# Generated by FakeRAM 2.0
VERSION 5.7 ;
BUSBITCHARS "[]" ;
PROPERTYDEFINITIONS
  MACRO width INTEGER ;
  MACRO depth INTEGER ;
  MACRO banks INTEGER ;
END PROPERTYDEFINITIONS
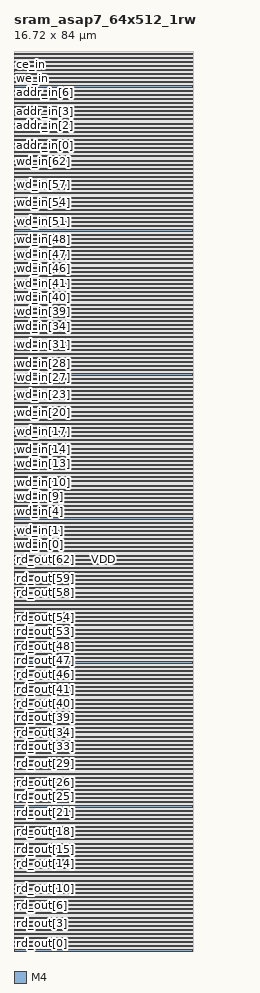
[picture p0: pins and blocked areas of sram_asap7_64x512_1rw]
MACRO sram_asap7_64x512_1rw
  PROPERTY width 64 ;
  PROPERTY depth 512 ;
  PROPERTY banks 2 ;
  FOREIGN sram_asap7_64x512_1rw 0 0 ;
  SYMMETRY X Y R90 ;
  SIZE 16.720 BY 84.000 ;
  CLASS BLOCK ;
  PIN rd_out[0]
    DIRECTION OUTPUT ;
    USE SIGNAL ;
    SHAPE ABUTMENT ;
    PORT
      LAYER M4 ;
      RECT 0.000 0.048 0.024 0.072 ;
    END
  END rd_out[0]
  PIN rd_out[1]
    DIRECTION OUTPUT ;
    USE SIGNAL ;
    SHAPE ABUTMENT ;
    PORT
      LAYER M4 ;
      RECT 0.000 0.624 0.024 0.648 ;
    END
  END rd_out[1]
  PIN rd_out[2]
    DIRECTION OUTPUT ;
    USE SIGNAL ;
    SHAPE ABUTMENT ;
    PORT
      LAYER M4 ;
      RECT 0.000 1.200 0.024 1.224 ;
    END
  END rd_out[2]
  PIN rd_out[3]
    DIRECTION OUTPUT ;
    USE SIGNAL ;
    SHAPE ABUTMENT ;
    PORT
      LAYER M4 ;
      RECT 0.000 1.776 0.024 1.800 ;
    END
  END rd_out[3]
  PIN rd_out[4]
    DIRECTION OUTPUT ;
    USE SIGNAL ;
    SHAPE ABUTMENT ;
    PORT
      LAYER M4 ;
      RECT 0.000 2.352 0.024 2.376 ;
    END
  END rd_out[4]
  PIN rd_out[5]
    DIRECTION OUTPUT ;
    USE SIGNAL ;
    SHAPE ABUTMENT ;
    PORT
      LAYER M4 ;
      RECT 0.000 2.928 0.024 2.952 ;
    END
  END rd_out[5]
  PIN rd_out[6]
    DIRECTION OUTPUT ;
    USE SIGNAL ;
    SHAPE ABUTMENT ;
    PORT
      LAYER M4 ;
      RECT 0.000 3.504 0.024 3.528 ;
    END
  END rd_out[6]
  PIN rd_out[7]
    DIRECTION OUTPUT ;
    USE SIGNAL ;
    SHAPE ABUTMENT ;
    PORT
      LAYER M4 ;
      RECT 0.000 4.080 0.024 4.104 ;
    END
  END rd_out[7]
  PIN rd_out[8]
    DIRECTION OUTPUT ;
    USE SIGNAL ;
    SHAPE ABUTMENT ;
    PORT
      LAYER M4 ;
      RECT 0.000 4.656 0.024 4.680 ;
    END
  END rd_out[8]
  PIN rd_out[9]
    DIRECTION OUTPUT ;
    USE SIGNAL ;
    SHAPE ABUTMENT ;
    PORT
      LAYER M4 ;
      RECT 0.000 5.232 0.024 5.256 ;
    END
  END rd_out[9]
  PIN rd_out[10]
    DIRECTION OUTPUT ;
    USE SIGNAL ;
    SHAPE ABUTMENT ;
    PORT
      LAYER M4 ;
      RECT 0.000 5.808 0.024 5.832 ;
    END
  END rd_out[10]
  PIN rd_out[11]
    DIRECTION OUTPUT ;
    USE SIGNAL ;
    SHAPE ABUTMENT ;
    PORT
      LAYER M4 ;
      RECT 0.000 6.384 0.024 6.408 ;
    END
  END rd_out[11]
  PIN rd_out[12]
    DIRECTION OUTPUT ;
    USE SIGNAL ;
    SHAPE ABUTMENT ;
    PORT
      LAYER M4 ;
      RECT 0.000 6.960 0.024 6.984 ;
    END
  END rd_out[12]
  PIN rd_out[13]
    DIRECTION OUTPUT ;
    USE SIGNAL ;
    SHAPE ABUTMENT ;
    PORT
      LAYER M4 ;
      RECT 0.000 7.536 0.024 7.560 ;
    END
  END rd_out[13]
  PIN rd_out[14]
    DIRECTION OUTPUT ;
    USE SIGNAL ;
    SHAPE ABUTMENT ;
    PORT
      LAYER M4 ;
      RECT 0.000 8.112 0.024 8.136 ;
    END
  END rd_out[14]
  PIN rd_out[15]
    DIRECTION OUTPUT ;
    USE SIGNAL ;
    SHAPE ABUTMENT ;
    PORT
      LAYER M4 ;
      RECT 0.000 8.688 0.024 8.712 ;
    END
  END rd_out[15]
  PIN rd_out[16]
    DIRECTION OUTPUT ;
    USE SIGNAL ;
    SHAPE ABUTMENT ;
    PORT
      LAYER M4 ;
      RECT 0.000 9.264 0.024 9.288 ;
    END
  END rd_out[16]
  PIN rd_out[17]
    DIRECTION OUTPUT ;
    USE SIGNAL ;
    SHAPE ABUTMENT ;
    PORT
      LAYER M4 ;
      RECT 0.000 9.840 0.024 9.864 ;
    END
  END rd_out[17]
  PIN rd_out[18]
    DIRECTION OUTPUT ;
    USE SIGNAL ;
    SHAPE ABUTMENT ;
    PORT
      LAYER M4 ;
      RECT 0.000 10.416 0.024 10.440 ;
    END
  END rd_out[18]
  PIN rd_out[19]
    DIRECTION OUTPUT ;
    USE SIGNAL ;
    SHAPE ABUTMENT ;
    PORT
      LAYER M4 ;
      RECT 0.000 10.992 0.024 11.016 ;
    END
  END rd_out[19]
  PIN rd_out[20]
    DIRECTION OUTPUT ;
    USE SIGNAL ;
    SHAPE ABUTMENT ;
    PORT
      LAYER M4 ;
      RECT 0.000 11.568 0.024 11.592 ;
    END
  END rd_out[20]
  PIN rd_out[21]
    DIRECTION OUTPUT ;
    USE SIGNAL ;
    SHAPE ABUTMENT ;
    PORT
      LAYER M4 ;
      RECT 0.000 12.144 0.024 12.168 ;
    END
  END rd_out[21]
  PIN rd_out[22]
    DIRECTION OUTPUT ;
    USE SIGNAL ;
    SHAPE ABUTMENT ;
    PORT
      LAYER M4 ;
      RECT 0.000 12.720 0.024 12.744 ;
    END
  END rd_out[22]
  PIN rd_out[23]
    DIRECTION OUTPUT ;
    USE SIGNAL ;
    SHAPE ABUTMENT ;
    PORT
      LAYER M4 ;
      RECT 0.000 13.296 0.024 13.320 ;
    END
  END rd_out[23]
  PIN rd_out[24]
    DIRECTION OUTPUT ;
    USE SIGNAL ;
    SHAPE ABUTMENT ;
    PORT
      LAYER M4 ;
      RECT 0.000 13.872 0.024 13.896 ;
    END
  END rd_out[24]
  PIN rd_out[25]
    DIRECTION OUTPUT ;
    USE SIGNAL ;
    SHAPE ABUTMENT ;
    PORT
      LAYER M4 ;
      RECT 0.000 14.448 0.024 14.472 ;
    END
  END rd_out[25]
  PIN rd_out[26]
    DIRECTION OUTPUT ;
    USE SIGNAL ;
    SHAPE ABUTMENT ;
    PORT
      LAYER M4 ;
      RECT 0.000 15.024 0.024 15.048 ;
    END
  END rd_out[26]
  PIN rd_out[27]
    DIRECTION OUTPUT ;
    USE SIGNAL ;
    SHAPE ABUTMENT ;
    PORT
      LAYER M4 ;
      RECT 0.000 15.600 0.024 15.624 ;
    END
  END rd_out[27]
  PIN rd_out[28]
    DIRECTION OUTPUT ;
    USE SIGNAL ;
    SHAPE ABUTMENT ;
    PORT
      LAYER M4 ;
      RECT 0.000 16.176 0.024 16.200 ;
    END
  END rd_out[28]
  PIN rd_out[29]
    DIRECTION OUTPUT ;
    USE SIGNAL ;
    SHAPE ABUTMENT ;
    PORT
      LAYER M4 ;
      RECT 0.000 16.752 0.024 16.776 ;
    END
  END rd_out[29]
  PIN rd_out[30]
    DIRECTION OUTPUT ;
    USE SIGNAL ;
    SHAPE ABUTMENT ;
    PORT
      LAYER M4 ;
      RECT 0.000 17.328 0.024 17.352 ;
    END
  END rd_out[30]
  PIN rd_out[31]
    DIRECTION OUTPUT ;
    USE SIGNAL ;
    SHAPE ABUTMENT ;
    PORT
      LAYER M4 ;
      RECT 0.000 17.904 0.024 17.928 ;
    END
  END rd_out[31]
  PIN rd_out[32]
    DIRECTION OUTPUT ;
    USE SIGNAL ;
    SHAPE ABUTMENT ;
    PORT
      LAYER M4 ;
      RECT 0.000 18.480 0.024 18.504 ;
    END
  END rd_out[32]
  PIN rd_out[33]
    DIRECTION OUTPUT ;
    USE SIGNAL ;
    SHAPE ABUTMENT ;
    PORT
      LAYER M4 ;
      RECT 0.000 19.056 0.024 19.080 ;
    END
  END rd_out[33]
  PIN rd_out[34]
    DIRECTION OUTPUT ;
    USE SIGNAL ;
    SHAPE ABUTMENT ;
    PORT
      LAYER M4 ;
      RECT 0.000 19.632 0.024 19.656 ;
    END
  END rd_out[34]
  PIN rd_out[35]
    DIRECTION OUTPUT ;
    USE SIGNAL ;
    SHAPE ABUTMENT ;
    PORT
      LAYER M4 ;
      RECT 0.000 20.208 0.024 20.232 ;
    END
  END rd_out[35]
  PIN rd_out[36]
    DIRECTION OUTPUT ;
    USE SIGNAL ;
    SHAPE ABUTMENT ;
    PORT
      LAYER M4 ;
      RECT 0.000 20.784 0.024 20.808 ;
    END
  END rd_out[36]
  PIN rd_out[37]
    DIRECTION OUTPUT ;
    USE SIGNAL ;
    SHAPE ABUTMENT ;
    PORT
      LAYER M4 ;
      RECT 0.000 21.360 0.024 21.384 ;
    END
  END rd_out[37]
  PIN rd_out[38]
    DIRECTION OUTPUT ;
    USE SIGNAL ;
    SHAPE ABUTMENT ;
    PORT
      LAYER M4 ;
      RECT 0.000 21.936 0.024 21.960 ;
    END
  END rd_out[38]
  PIN rd_out[39]
    DIRECTION OUTPUT ;
    USE SIGNAL ;
    SHAPE ABUTMENT ;
    PORT
      LAYER M4 ;
      RECT 0.000 22.512 0.024 22.536 ;
    END
  END rd_out[39]
  PIN rd_out[40]
    DIRECTION OUTPUT ;
    USE SIGNAL ;
    SHAPE ABUTMENT ;
    PORT
      LAYER M4 ;
      RECT 0.000 23.088 0.024 23.112 ;
    END
  END rd_out[40]
  PIN rd_out[41]
    DIRECTION OUTPUT ;
    USE SIGNAL ;
    SHAPE ABUTMENT ;
    PORT
      LAYER M4 ;
      RECT 0.000 23.664 0.024 23.688 ;
    END
  END rd_out[41]
  PIN rd_out[42]
    DIRECTION OUTPUT ;
    USE SIGNAL ;
    SHAPE ABUTMENT ;
    PORT
      LAYER M4 ;
      RECT 0.000 24.240 0.024 24.264 ;
    END
  END rd_out[42]
  PIN rd_out[43]
    DIRECTION OUTPUT ;
    USE SIGNAL ;
    SHAPE ABUTMENT ;
    PORT
      LAYER M4 ;
      RECT 0.000 24.816 0.024 24.840 ;
    END
  END rd_out[43]
  PIN rd_out[44]
    DIRECTION OUTPUT ;
    USE SIGNAL ;
    SHAPE ABUTMENT ;
    PORT
      LAYER M4 ;
      RECT 0.000 25.392 0.024 25.416 ;
    END
  END rd_out[44]
  PIN rd_out[45]
    DIRECTION OUTPUT ;
    USE SIGNAL ;
    SHAPE ABUTMENT ;
    PORT
      LAYER M4 ;
      RECT 0.000 25.968 0.024 25.992 ;
    END
  END rd_out[45]
  PIN rd_out[46]
    DIRECTION OUTPUT ;
    USE SIGNAL ;
    SHAPE ABUTMENT ;
    PORT
      LAYER M4 ;
      RECT 0.000 26.544 0.024 26.568 ;
    END
  END rd_out[46]
  PIN rd_out[47]
    DIRECTION OUTPUT ;
    USE SIGNAL ;
    SHAPE ABUTMENT ;
    PORT
      LAYER M4 ;
      RECT 0.000 27.120 0.024 27.144 ;
    END
  END rd_out[47]
  PIN rd_out[48]
    DIRECTION OUTPUT ;
    USE SIGNAL ;
    SHAPE ABUTMENT ;
    PORT
      LAYER M4 ;
      RECT 0.000 27.696 0.024 27.720 ;
    END
  END rd_out[48]
  PIN rd_out[49]
    DIRECTION OUTPUT ;
    USE SIGNAL ;
    SHAPE ABUTMENT ;
    PORT
      LAYER M4 ;
      RECT 0.000 28.272 0.024 28.296 ;
    END
  END rd_out[49]
  PIN rd_out[50]
    DIRECTION OUTPUT ;
    USE SIGNAL ;
    SHAPE ABUTMENT ;
    PORT
      LAYER M4 ;
      RECT 0.000 28.848 0.024 28.872 ;
    END
  END rd_out[50]
  PIN rd_out[51]
    DIRECTION OUTPUT ;
    USE SIGNAL ;
    SHAPE ABUTMENT ;
    PORT
      LAYER M4 ;
      RECT 0.000 29.424 0.024 29.448 ;
    END
  END rd_out[51]
  PIN rd_out[52]
    DIRECTION OUTPUT ;
    USE SIGNAL ;
    SHAPE ABUTMENT ;
    PORT
      LAYER M4 ;
      RECT 0.000 30.000 0.024 30.024 ;
    END
  END rd_out[52]
  PIN rd_out[53]
    DIRECTION OUTPUT ;
    USE SIGNAL ;
    SHAPE ABUTMENT ;
    PORT
      LAYER M4 ;
      RECT 0.000 30.576 0.024 30.600 ;
    END
  END rd_out[53]
  PIN rd_out[54]
    DIRECTION OUTPUT ;
    USE SIGNAL ;
    SHAPE ABUTMENT ;
    PORT
      LAYER M4 ;
      RECT 0.000 31.152 0.024 31.176 ;
    END
  END rd_out[54]
  PIN rd_out[55]
    DIRECTION OUTPUT ;
    USE SIGNAL ;
    SHAPE ABUTMENT ;
    PORT
      LAYER M4 ;
      RECT 0.000 31.728 0.024 31.752 ;
    END
  END rd_out[55]
  PIN rd_out[56]
    DIRECTION OUTPUT ;
    USE SIGNAL ;
    SHAPE ABUTMENT ;
    PORT
      LAYER M4 ;
      RECT 0.000 32.304 0.024 32.328 ;
    END
  END rd_out[56]
  PIN rd_out[57]
    DIRECTION OUTPUT ;
    USE SIGNAL ;
    SHAPE ABUTMENT ;
    PORT
      LAYER M4 ;
      RECT 0.000 32.880 0.024 32.904 ;
    END
  END rd_out[57]
  PIN rd_out[58]
    DIRECTION OUTPUT ;
    USE SIGNAL ;
    SHAPE ABUTMENT ;
    PORT
      LAYER M4 ;
      RECT 0.000 33.456 0.024 33.480 ;
    END
  END rd_out[58]
  PIN rd_out[59]
    DIRECTION OUTPUT ;
    USE SIGNAL ;
    SHAPE ABUTMENT ;
    PORT
      LAYER M4 ;
      RECT 0.000 34.032 0.024 34.056 ;
    END
  END rd_out[59]
  PIN rd_out[60]
    DIRECTION OUTPUT ;
    USE SIGNAL ;
    SHAPE ABUTMENT ;
    PORT
      LAYER M4 ;
      RECT 0.000 34.608 0.024 34.632 ;
    END
  END rd_out[60]
  PIN rd_out[61]
    DIRECTION OUTPUT ;
    USE SIGNAL ;
    SHAPE ABUTMENT ;
    PORT
      LAYER M4 ;
      RECT 0.000 35.184 0.024 35.208 ;
    END
  END rd_out[61]
  PIN rd_out[62]
    DIRECTION OUTPUT ;
    USE SIGNAL ;
    SHAPE ABUTMENT ;
    PORT
      LAYER M4 ;
      RECT 0.000 35.760 0.024 35.784 ;
    END
  END rd_out[62]
  PIN rd_out[63]
    DIRECTION OUTPUT ;
    USE SIGNAL ;
    SHAPE ABUTMENT ;
    PORT
      LAYER M4 ;
      RECT 0.000 36.336 0.024 36.360 ;
    END
  END rd_out[63]
  PIN wd_in[0]
    DIRECTION INPUT ;
    USE SIGNAL ;
    SHAPE ABUTMENT ;
    PORT
      LAYER M4 ;
      RECT 0.000 37.968 0.024 37.992 ;
    END
  END wd_in[0]
  PIN wd_in[1]
    DIRECTION INPUT ;
    USE SIGNAL ;
    SHAPE ABUTMENT ;
    PORT
      LAYER M4 ;
      RECT 0.000 38.544 0.024 38.568 ;
    END
  END wd_in[1]
  PIN wd_in[2]
    DIRECTION INPUT ;
    USE SIGNAL ;
    SHAPE ABUTMENT ;
    PORT
      LAYER M4 ;
      RECT 0.000 39.120 0.024 39.144 ;
    END
  END wd_in[2]
  PIN wd_in[3]
    DIRECTION INPUT ;
    USE SIGNAL ;
    SHAPE ABUTMENT ;
    PORT
      LAYER M4 ;
      RECT 0.000 39.696 0.024 39.720 ;
    END
  END wd_in[3]
  PIN wd_in[4]
    DIRECTION INPUT ;
    USE SIGNAL ;
    SHAPE ABUTMENT ;
    PORT
      LAYER M4 ;
      RECT 0.000 40.272 0.024 40.296 ;
    END
  END wd_in[4]
  PIN wd_in[5]
    DIRECTION INPUT ;
    USE SIGNAL ;
    SHAPE ABUTMENT ;
    PORT
      LAYER M4 ;
      RECT 0.000 40.848 0.024 40.872 ;
    END
  END wd_in[5]
  PIN wd_in[6]
    DIRECTION INPUT ;
    USE SIGNAL ;
    SHAPE ABUTMENT ;
    PORT
      LAYER M4 ;
      RECT 0.000 41.424 0.024 41.448 ;
    END
  END wd_in[6]
  PIN wd_in[7]
    DIRECTION INPUT ;
    USE SIGNAL ;
    SHAPE ABUTMENT ;
    PORT
      LAYER M4 ;
      RECT 0.000 42.000 0.024 42.024 ;
    END
  END wd_in[7]
  PIN wd_in[8]
    DIRECTION INPUT ;
    USE SIGNAL ;
    SHAPE ABUTMENT ;
    PORT
      LAYER M4 ;
      RECT 0.000 42.576 0.024 42.600 ;
    END
  END wd_in[8]
  PIN wd_in[9]
    DIRECTION INPUT ;
    USE SIGNAL ;
    SHAPE ABUTMENT ;
    PORT
      LAYER M4 ;
      RECT 0.000 43.152 0.024 43.176 ;
    END
  END wd_in[9]
  PIN wd_in[10]
    DIRECTION INPUT ;
    USE SIGNAL ;
    SHAPE ABUTMENT ;
    PORT
      LAYER M4 ;
      RECT 0.000 43.728 0.024 43.752 ;
    END
  END wd_in[10]
  PIN wd_in[11]
    DIRECTION INPUT ;
    USE SIGNAL ;
    SHAPE ABUTMENT ;
    PORT
      LAYER M4 ;
      RECT 0.000 44.304 0.024 44.328 ;
    END
  END wd_in[11]
  PIN wd_in[12]
    DIRECTION INPUT ;
    USE SIGNAL ;
    SHAPE ABUTMENT ;
    PORT
      LAYER M4 ;
      RECT 0.000 44.880 0.024 44.904 ;
    END
  END wd_in[12]
  PIN wd_in[13]
    DIRECTION INPUT ;
    USE SIGNAL ;
    SHAPE ABUTMENT ;
    PORT
      LAYER M4 ;
      RECT 0.000 45.456 0.024 45.480 ;
    END
  END wd_in[13]
  PIN wd_in[14]
    DIRECTION INPUT ;
    USE SIGNAL ;
    SHAPE ABUTMENT ;
    PORT
      LAYER M4 ;
      RECT 0.000 46.032 0.024 46.056 ;
    END
  END wd_in[14]
  PIN wd_in[15]
    DIRECTION INPUT ;
    USE SIGNAL ;
    SHAPE ABUTMENT ;
    PORT
      LAYER M4 ;
      RECT 0.000 46.608 0.024 46.632 ;
    END
  END wd_in[15]
  PIN wd_in[16]
    DIRECTION INPUT ;
    USE SIGNAL ;
    SHAPE ABUTMENT ;
    PORT
      LAYER M4 ;
      RECT 0.000 47.184 0.024 47.208 ;
    END
  END wd_in[16]
  PIN wd_in[17]
    DIRECTION INPUT ;
    USE SIGNAL ;
    SHAPE ABUTMENT ;
    PORT
      LAYER M4 ;
      RECT 0.000 47.760 0.024 47.784 ;
    END
  END wd_in[17]
  PIN wd_in[18]
    DIRECTION INPUT ;
    USE SIGNAL ;
    SHAPE ABUTMENT ;
    PORT
      LAYER M4 ;
      RECT 0.000 48.336 0.024 48.360 ;
    END
  END wd_in[18]
  PIN wd_in[19]
    DIRECTION INPUT ;
    USE SIGNAL ;
    SHAPE ABUTMENT ;
    PORT
      LAYER M4 ;
      RECT 0.000 48.912 0.024 48.936 ;
    END
  END wd_in[19]
  PIN wd_in[20]
    DIRECTION INPUT ;
    USE SIGNAL ;
    SHAPE ABUTMENT ;
    PORT
      LAYER M4 ;
      RECT 0.000 49.488 0.024 49.512 ;
    END
  END wd_in[20]
  PIN wd_in[21]
    DIRECTION INPUT ;
    USE SIGNAL ;
    SHAPE ABUTMENT ;
    PORT
      LAYER M4 ;
      RECT 0.000 50.064 0.024 50.088 ;
    END
  END wd_in[21]
  PIN wd_in[22]
    DIRECTION INPUT ;
    USE SIGNAL ;
    SHAPE ABUTMENT ;
    PORT
      LAYER M4 ;
      RECT 0.000 50.640 0.024 50.664 ;
    END
  END wd_in[22]
  PIN wd_in[23]
    DIRECTION INPUT ;
    USE SIGNAL ;
    SHAPE ABUTMENT ;
    PORT
      LAYER M4 ;
      RECT 0.000 51.216 0.024 51.240 ;
    END
  END wd_in[23]
  PIN wd_in[24]
    DIRECTION INPUT ;
    USE SIGNAL ;
    SHAPE ABUTMENT ;
    PORT
      LAYER M4 ;
      RECT 0.000 51.792 0.024 51.816 ;
    END
  END wd_in[24]
  PIN wd_in[25]
    DIRECTION INPUT ;
    USE SIGNAL ;
    SHAPE ABUTMENT ;
    PORT
      LAYER M4 ;
      RECT 0.000 52.368 0.024 52.392 ;
    END
  END wd_in[25]
  PIN wd_in[26]
    DIRECTION INPUT ;
    USE SIGNAL ;
    SHAPE ABUTMENT ;
    PORT
      LAYER M4 ;
      RECT 0.000 52.944 0.024 52.968 ;
    END
  END wd_in[26]
  PIN wd_in[27]
    DIRECTION INPUT ;
    USE SIGNAL ;
    SHAPE ABUTMENT ;
    PORT
      LAYER M4 ;
      RECT 0.000 53.520 0.024 53.544 ;
    END
  END wd_in[27]
  PIN wd_in[28]
    DIRECTION INPUT ;
    USE SIGNAL ;
    SHAPE ABUTMENT ;
    PORT
      LAYER M4 ;
      RECT 0.000 54.096 0.024 54.120 ;
    END
  END wd_in[28]
  PIN wd_in[29]
    DIRECTION INPUT ;
    USE SIGNAL ;
    SHAPE ABUTMENT ;
    PORT
      LAYER M4 ;
      RECT 0.000 54.672 0.024 54.696 ;
    END
  END wd_in[29]
  PIN wd_in[30]
    DIRECTION INPUT ;
    USE SIGNAL ;
    SHAPE ABUTMENT ;
    PORT
      LAYER M4 ;
      RECT 0.000 55.248 0.024 55.272 ;
    END
  END wd_in[30]
  PIN wd_in[31]
    DIRECTION INPUT ;
    USE SIGNAL ;
    SHAPE ABUTMENT ;
    PORT
      LAYER M4 ;
      RECT 0.000 55.824 0.024 55.848 ;
    END
  END wd_in[31]
  PIN wd_in[32]
    DIRECTION INPUT ;
    USE SIGNAL ;
    SHAPE ABUTMENT ;
    PORT
      LAYER M4 ;
      RECT 0.000 56.400 0.024 56.424 ;
    END
  END wd_in[32]
  PIN wd_in[33]
    DIRECTION INPUT ;
    USE SIGNAL ;
    SHAPE ABUTMENT ;
    PORT
      LAYER M4 ;
      RECT 0.000 56.976 0.024 57.000 ;
    END
  END wd_in[33]
  PIN wd_in[34]
    DIRECTION INPUT ;
    USE SIGNAL ;
    SHAPE ABUTMENT ;
    PORT
      LAYER M4 ;
      RECT 0.000 57.552 0.024 57.576 ;
    END
  END wd_in[34]
  PIN wd_in[35]
    DIRECTION INPUT ;
    USE SIGNAL ;
    SHAPE ABUTMENT ;
    PORT
      LAYER M4 ;
      RECT 0.000 58.128 0.024 58.152 ;
    END
  END wd_in[35]
  PIN wd_in[36]
    DIRECTION INPUT ;
    USE SIGNAL ;
    SHAPE ABUTMENT ;
    PORT
      LAYER M4 ;
      RECT 0.000 58.704 0.024 58.728 ;
    END
  END wd_in[36]
  PIN wd_in[37]
    DIRECTION INPUT ;
    USE SIGNAL ;
    SHAPE ABUTMENT ;
    PORT
      LAYER M4 ;
      RECT 0.000 59.280 0.024 59.304 ;
    END
  END wd_in[37]
  PIN wd_in[38]
    DIRECTION INPUT ;
    USE SIGNAL ;
    SHAPE ABUTMENT ;
    PORT
      LAYER M4 ;
      RECT 0.000 59.856 0.024 59.880 ;
    END
  END wd_in[38]
  PIN wd_in[39]
    DIRECTION INPUT ;
    USE SIGNAL ;
    SHAPE ABUTMENT ;
    PORT
      LAYER M4 ;
      RECT 0.000 60.432 0.024 60.456 ;
    END
  END wd_in[39]
  PIN wd_in[40]
    DIRECTION INPUT ;
    USE SIGNAL ;
    SHAPE ABUTMENT ;
    PORT
      LAYER M4 ;
      RECT 0.000 61.008 0.024 61.032 ;
    END
  END wd_in[40]
  PIN wd_in[41]
    DIRECTION INPUT ;
    USE SIGNAL ;
    SHAPE ABUTMENT ;
    PORT
      LAYER M4 ;
      RECT 0.000 61.584 0.024 61.608 ;
    END
  END wd_in[41]
  PIN wd_in[42]
    DIRECTION INPUT ;
    USE SIGNAL ;
    SHAPE ABUTMENT ;
    PORT
      LAYER M4 ;
      RECT 0.000 62.160 0.024 62.184 ;
    END
  END wd_in[42]
  PIN wd_in[43]
    DIRECTION INPUT ;
    USE SIGNAL ;
    SHAPE ABUTMENT ;
    PORT
      LAYER M4 ;
      RECT 0.000 62.736 0.024 62.760 ;
    END
  END wd_in[43]
  PIN wd_in[44]
    DIRECTION INPUT ;
    USE SIGNAL ;
    SHAPE ABUTMENT ;
    PORT
      LAYER M4 ;
      RECT 0.000 63.312 0.024 63.336 ;
    END
  END wd_in[44]
  PIN wd_in[45]
    DIRECTION INPUT ;
    USE SIGNAL ;
    SHAPE ABUTMENT ;
    PORT
      LAYER M4 ;
      RECT 0.000 63.888 0.024 63.912 ;
    END
  END wd_in[45]
  PIN wd_in[46]
    DIRECTION INPUT ;
    USE SIGNAL ;
    SHAPE ABUTMENT ;
    PORT
      LAYER M4 ;
      RECT 0.000 64.464 0.024 64.488 ;
    END
  END wd_in[46]
  PIN wd_in[47]
    DIRECTION INPUT ;
    USE SIGNAL ;
    SHAPE ABUTMENT ;
    PORT
      LAYER M4 ;
      RECT 0.000 65.040 0.024 65.064 ;
    END
  END wd_in[47]
  PIN wd_in[48]
    DIRECTION INPUT ;
    USE SIGNAL ;
    SHAPE ABUTMENT ;
    PORT
      LAYER M4 ;
      RECT 0.000 65.616 0.024 65.640 ;
    END
  END wd_in[48]
  PIN wd_in[49]
    DIRECTION INPUT ;
    USE SIGNAL ;
    SHAPE ABUTMENT ;
    PORT
      LAYER M4 ;
      RECT 0.000 66.192 0.024 66.216 ;
    END
  END wd_in[49]
  PIN wd_in[50]
    DIRECTION INPUT ;
    USE SIGNAL ;
    SHAPE ABUTMENT ;
    PORT
      LAYER M4 ;
      RECT 0.000 66.768 0.024 66.792 ;
    END
  END wd_in[50]
  PIN wd_in[51]
    DIRECTION INPUT ;
    USE SIGNAL ;
    SHAPE ABUTMENT ;
    PORT
      LAYER M4 ;
      RECT 0.000 67.344 0.024 67.368 ;
    END
  END wd_in[51]
  PIN wd_in[52]
    DIRECTION INPUT ;
    USE SIGNAL ;
    SHAPE ABUTMENT ;
    PORT
      LAYER M4 ;
      RECT 0.000 67.920 0.024 67.944 ;
    END
  END wd_in[52]
  PIN wd_in[53]
    DIRECTION INPUT ;
    USE SIGNAL ;
    SHAPE ABUTMENT ;
    PORT
      LAYER M4 ;
      RECT 0.000 68.496 0.024 68.520 ;
    END
  END wd_in[53]
  PIN wd_in[54]
    DIRECTION INPUT ;
    USE SIGNAL ;
    SHAPE ABUTMENT ;
    PORT
      LAYER M4 ;
      RECT 0.000 69.072 0.024 69.096 ;
    END
  END wd_in[54]
  PIN wd_in[55]
    DIRECTION INPUT ;
    USE SIGNAL ;
    SHAPE ABUTMENT ;
    PORT
      LAYER M4 ;
      RECT 0.000 69.648 0.024 69.672 ;
    END
  END wd_in[55]
  PIN wd_in[56]
    DIRECTION INPUT ;
    USE SIGNAL ;
    SHAPE ABUTMENT ;
    PORT
      LAYER M4 ;
      RECT 0.000 70.224 0.024 70.248 ;
    END
  END wd_in[56]
  PIN wd_in[57]
    DIRECTION INPUT ;
    USE SIGNAL ;
    SHAPE ABUTMENT ;
    PORT
      LAYER M4 ;
      RECT 0.000 70.800 0.024 70.824 ;
    END
  END wd_in[57]
  PIN wd_in[58]
    DIRECTION INPUT ;
    USE SIGNAL ;
    SHAPE ABUTMENT ;
    PORT
      LAYER M4 ;
      RECT 0.000 71.376 0.024 71.400 ;
    END
  END wd_in[58]
  PIN wd_in[59]
    DIRECTION INPUT ;
    USE SIGNAL ;
    SHAPE ABUTMENT ;
    PORT
      LAYER M4 ;
      RECT 0.000 71.952 0.024 71.976 ;
    END
  END wd_in[59]
  PIN wd_in[60]
    DIRECTION INPUT ;
    USE SIGNAL ;
    SHAPE ABUTMENT ;
    PORT
      LAYER M4 ;
      RECT 0.000 72.528 0.024 72.552 ;
    END
  END wd_in[60]
  PIN wd_in[61]
    DIRECTION INPUT ;
    USE SIGNAL ;
    SHAPE ABUTMENT ;
    PORT
      LAYER M4 ;
      RECT 0.000 73.104 0.024 73.128 ;
    END
  END wd_in[61]
  PIN wd_in[62]
    DIRECTION INPUT ;
    USE SIGNAL ;
    SHAPE ABUTMENT ;
    PORT
      LAYER M4 ;
      RECT 0.000 73.680 0.024 73.704 ;
    END
  END wd_in[62]
  PIN wd_in[63]
    DIRECTION INPUT ;
    USE SIGNAL ;
    SHAPE ABUTMENT ;
    PORT
      LAYER M4 ;
      RECT 0.000 74.256 0.024 74.280 ;
    END
  END wd_in[63]
  PIN addr_in[0]
    DIRECTION INPUT ;
    USE SIGNAL ;
    SHAPE ABUTMENT ;
    PORT
      LAYER M4 ;
      RECT 0.000 75.888 0.024 75.912 ;
    END
  END addr_in[0]
  PIN addr_in[1]
    DIRECTION INPUT ;
    USE SIGNAL ;
    SHAPE ABUTMENT ;
    PORT
      LAYER M4 ;
      RECT 0.000 76.464 0.024 76.488 ;
    END
  END addr_in[1]
  PIN addr_in[2]
    DIRECTION INPUT ;
    USE SIGNAL ;
    SHAPE ABUTMENT ;
    PORT
      LAYER M4 ;
      RECT 0.000 77.040 0.024 77.064 ;
    END
  END addr_in[2]
  PIN addr_in[3]
    DIRECTION INPUT ;
    USE SIGNAL ;
    SHAPE ABUTMENT ;
    PORT
      LAYER M4 ;
      RECT 0.000 77.616 0.024 77.640 ;
    END
  END addr_in[3]
  PIN addr_in[4]
    DIRECTION INPUT ;
    USE SIGNAL ;
    SHAPE ABUTMENT ;
    PORT
      LAYER M4 ;
      RECT 0.000 78.192 0.024 78.216 ;
    END
  END addr_in[4]
  PIN addr_in[5]
    DIRECTION INPUT ;
    USE SIGNAL ;
    SHAPE ABUTMENT ;
    PORT
      LAYER M4 ;
      RECT 0.000 78.768 0.024 78.792 ;
    END
  END addr_in[5]
  PIN addr_in[6]
    DIRECTION INPUT ;
    USE SIGNAL ;
    SHAPE ABUTMENT ;
    PORT
      LAYER M4 ;
      RECT 0.000 79.344 0.024 79.368 ;
    END
  END addr_in[6]
  PIN addr_in[7]
    DIRECTION INPUT ;
    USE SIGNAL ;
    SHAPE ABUTMENT ;
    PORT
      LAYER M4 ;
      RECT 0.000 79.920 0.024 79.944 ;
    END
  END addr_in[7]
  PIN addr_in[8]
    DIRECTION INPUT ;
    USE SIGNAL ;
    SHAPE ABUTMENT ;
    PORT
      LAYER M4 ;
      RECT 0.000 80.496 0.024 80.520 ;
    END
  END addr_in[8]
  PIN we_in
    DIRECTION INPUT ;
    USE SIGNAL ;
    SHAPE ABUTMENT ;
    PORT
      LAYER M4 ;
      RECT 0.000 82.128 0.024 82.152 ;
    END
  END we_in
  PIN ce_in
    DIRECTION INPUT ;
    USE SIGNAL ;
    SHAPE ABUTMENT ;
    PORT
      LAYER M4 ;
      RECT 0.000 82.704 0.024 82.728 ;
    END
  END ce_in
  PIN clk
    DIRECTION INPUT ;
    USE SIGNAL ;
    SHAPE ABUTMENT ;
    PORT
      LAYER M4 ;
      RECT 0.000 83.280 0.024 83.304 ;
    END
  END clk
  PIN VSS
    DIRECTION INOUT ;
    USE GROUND ;
    PORT
      LAYER M4 ;
      RECT 0.048 0.000 16.672 0.096 ;
      RECT 0.048 0.768 16.672 0.864 ;
      RECT 0.048 1.536 16.672 1.632 ;
      RECT 0.048 2.304 16.672 2.400 ;
      RECT 0.048 3.072 16.672 3.168 ;
      RECT 0.048 3.840 16.672 3.936 ;
      RECT 0.048 4.608 16.672 4.704 ;
      RECT 0.048 5.376 16.672 5.472 ;
      RECT 0.048 6.144 16.672 6.240 ;
      RECT 0.048 6.912 16.672 7.008 ;
      RECT 0.048 7.680 16.672 7.776 ;
      RECT 0.048 8.448 16.672 8.544 ;
      RECT 0.048 9.216 16.672 9.312 ;
      RECT 0.048 9.984 16.672 10.080 ;
      RECT 0.048 10.752 16.672 10.848 ;
      RECT 0.048 11.520 16.672 11.616 ;
      RECT 0.048 12.288 16.672 12.384 ;
      RECT 0.048 13.056 16.672 13.152 ;
      RECT 0.048 13.824 16.672 13.920 ;
      RECT 0.048 14.592 16.672 14.688 ;
      RECT 0.048 15.360 16.672 15.456 ;
      RECT 0.048 16.128 16.672 16.224 ;
      RECT 0.048 16.896 16.672 16.992 ;
      RECT 0.048 17.664 16.672 17.760 ;
      RECT 0.048 18.432 16.672 18.528 ;
      RECT 0.048 19.200 16.672 19.296 ;
      RECT 0.048 19.968 16.672 20.064 ;
      RECT 0.048 20.736 16.672 20.832 ;
      RECT 0.048 21.504 16.672 21.600 ;
      RECT 0.048 22.272 16.672 22.368 ;
      RECT 0.048 23.040 16.672 23.136 ;
      RECT 0.048 23.808 16.672 23.904 ;
      RECT 0.048 24.576 16.672 24.672 ;
      RECT 0.048 25.344 16.672 25.440 ;
      RECT 0.048 26.112 16.672 26.208 ;
      RECT 0.048 26.880 16.672 26.976 ;
      RECT 0.048 27.648 16.672 27.744 ;
      RECT 0.048 28.416 16.672 28.512 ;
      RECT 0.048 29.184 16.672 29.280 ;
      RECT 0.048 29.952 16.672 30.048 ;
      RECT 0.048 30.720 16.672 30.816 ;
      RECT 0.048 31.488 16.672 31.584 ;
      RECT 0.048 32.256 16.672 32.352 ;
      RECT 0.048 33.024 16.672 33.120 ;
      RECT 0.048 33.792 16.672 33.888 ;
      RECT 0.048 34.560 16.672 34.656 ;
      RECT 0.048 35.328 16.672 35.424 ;
      RECT 0.048 36.096 16.672 36.192 ;
      RECT 0.048 36.864 16.672 36.960 ;
      RECT 0.048 37.632 16.672 37.728 ;
      RECT 0.048 38.400 16.672 38.496 ;
      RECT 0.048 39.168 16.672 39.264 ;
      RECT 0.048 39.936 16.672 40.032 ;
      RECT 0.048 40.704 16.672 40.800 ;
      RECT 0.048 41.472 16.672 41.568 ;
      RECT 0.048 42.240 16.672 42.336 ;
      RECT 0.048 43.008 16.672 43.104 ;
      RECT 0.048 43.776 16.672 43.872 ;
      RECT 0.048 44.544 16.672 44.640 ;
      RECT 0.048 45.312 16.672 45.408 ;
      RECT 0.048 46.080 16.672 46.176 ;
      RECT 0.048 46.848 16.672 46.944 ;
      RECT 0.048 47.616 16.672 47.712 ;
      RECT 0.048 48.384 16.672 48.480 ;
      RECT 0.048 49.152 16.672 49.248 ;
      RECT 0.048 49.920 16.672 50.016 ;
      RECT 0.048 50.688 16.672 50.784 ;
      RECT 0.048 51.456 16.672 51.552 ;
      RECT 0.048 52.224 16.672 52.320 ;
      RECT 0.048 52.992 16.672 53.088 ;
      RECT 0.048 53.760 16.672 53.856 ;
      RECT 0.048 54.528 16.672 54.624 ;
      RECT 0.048 55.296 16.672 55.392 ;
      RECT 0.048 56.064 16.672 56.160 ;
      RECT 0.048 56.832 16.672 56.928 ;
      RECT 0.048 57.600 16.672 57.696 ;
      RECT 0.048 58.368 16.672 58.464 ;
      RECT 0.048 59.136 16.672 59.232 ;
      RECT 0.048 59.904 16.672 60.000 ;
      RECT 0.048 60.672 16.672 60.768 ;
      RECT 0.048 61.440 16.672 61.536 ;
      RECT 0.048 62.208 16.672 62.304 ;
      RECT 0.048 62.976 16.672 63.072 ;
      RECT 0.048 63.744 16.672 63.840 ;
      RECT 0.048 64.512 16.672 64.608 ;
      RECT 0.048 65.280 16.672 65.376 ;
      RECT 0.048 66.048 16.672 66.144 ;
      RECT 0.048 66.816 16.672 66.912 ;
      RECT 0.048 67.584 16.672 67.680 ;
      RECT 0.048 68.352 16.672 68.448 ;
      RECT 0.048 69.120 16.672 69.216 ;
      RECT 0.048 69.888 16.672 69.984 ;
      RECT 0.048 70.656 16.672 70.752 ;
      RECT 0.048 71.424 16.672 71.520 ;
      RECT 0.048 72.192 16.672 72.288 ;
      RECT 0.048 72.960 16.672 73.056 ;
      RECT 0.048 73.728 16.672 73.824 ;
      RECT 0.048 74.496 16.672 74.592 ;
      RECT 0.048 75.264 16.672 75.360 ;
      RECT 0.048 76.032 16.672 76.128 ;
      RECT 0.048 76.800 16.672 76.896 ;
      RECT 0.048 77.568 16.672 77.664 ;
      RECT 0.048 78.336 16.672 78.432 ;
      RECT 0.048 79.104 16.672 79.200 ;
      RECT 0.048 79.872 16.672 79.968 ;
      RECT 0.048 80.640 16.672 80.736 ;
      RECT 0.048 81.408 16.672 81.504 ;
      RECT 0.048 82.176 16.672 82.272 ;
      RECT 0.048 82.944 16.672 83.040 ;
      RECT 0.048 83.712 16.672 83.808 ;
    END
  END VSS
  PIN VDD
    DIRECTION INOUT ;
    USE POWER ;
    PORT
      LAYER M4 ;
      RECT 0.048 0.384 16.672 0.480 ;
      RECT 0.048 1.152 16.672 1.248 ;
      RECT 0.048 1.920 16.672 2.016 ;
      RECT 0.048 2.688 16.672 2.784 ;
      RECT 0.048 3.456 16.672 3.552 ;
      RECT 0.048 4.224 16.672 4.320 ;
      RECT 0.048 4.992 16.672 5.088 ;
      RECT 0.048 5.760 16.672 5.856 ;
      RECT 0.048 6.528 16.672 6.624 ;
      RECT 0.048 7.296 16.672 7.392 ;
      RECT 0.048 8.064 16.672 8.160 ;
      RECT 0.048 8.832 16.672 8.928 ;
      RECT 0.048 9.600 16.672 9.696 ;
      RECT 0.048 10.368 16.672 10.464 ;
      RECT 0.048 11.136 16.672 11.232 ;
      RECT 0.048 11.904 16.672 12.000 ;
      RECT 0.048 12.672 16.672 12.768 ;
      RECT 0.048 13.440 16.672 13.536 ;
      RECT 0.048 14.208 16.672 14.304 ;
      RECT 0.048 14.976 16.672 15.072 ;
      RECT 0.048 15.744 16.672 15.840 ;
      RECT 0.048 16.512 16.672 16.608 ;
      RECT 0.048 17.280 16.672 17.376 ;
      RECT 0.048 18.048 16.672 18.144 ;
      RECT 0.048 18.816 16.672 18.912 ;
      RECT 0.048 19.584 16.672 19.680 ;
      RECT 0.048 20.352 16.672 20.448 ;
      RECT 0.048 21.120 16.672 21.216 ;
      RECT 0.048 21.888 16.672 21.984 ;
      RECT 0.048 22.656 16.672 22.752 ;
      RECT 0.048 23.424 16.672 23.520 ;
      RECT 0.048 24.192 16.672 24.288 ;
      RECT 0.048 24.960 16.672 25.056 ;
      RECT 0.048 25.728 16.672 25.824 ;
      RECT 0.048 26.496 16.672 26.592 ;
      RECT 0.048 27.264 16.672 27.360 ;
      RECT 0.048 28.032 16.672 28.128 ;
      RECT 0.048 28.800 16.672 28.896 ;
      RECT 0.048 29.568 16.672 29.664 ;
      RECT 0.048 30.336 16.672 30.432 ;
      RECT 0.048 31.104 16.672 31.200 ;
      RECT 0.048 31.872 16.672 31.968 ;
      RECT 0.048 32.640 16.672 32.736 ;
      RECT 0.048 33.408 16.672 33.504 ;
      RECT 0.048 34.176 16.672 34.272 ;
      RECT 0.048 34.944 16.672 35.040 ;
      RECT 0.048 35.712 16.672 35.808 ;
      RECT 0.048 36.480 16.672 36.576 ;
      RECT 0.048 37.248 16.672 37.344 ;
      RECT 0.048 38.016 16.672 38.112 ;
      RECT 0.048 38.784 16.672 38.880 ;
      RECT 0.048 39.552 16.672 39.648 ;
      RECT 0.048 40.320 16.672 40.416 ;
      RECT 0.048 41.088 16.672 41.184 ;
      RECT 0.048 41.856 16.672 41.952 ;
      RECT 0.048 42.624 16.672 42.720 ;
      RECT 0.048 43.392 16.672 43.488 ;
      RECT 0.048 44.160 16.672 44.256 ;
      RECT 0.048 44.928 16.672 45.024 ;
      RECT 0.048 45.696 16.672 45.792 ;
      RECT 0.048 46.464 16.672 46.560 ;
      RECT 0.048 47.232 16.672 47.328 ;
      RECT 0.048 48.000 16.672 48.096 ;
      RECT 0.048 48.768 16.672 48.864 ;
      RECT 0.048 49.536 16.672 49.632 ;
      RECT 0.048 50.304 16.672 50.400 ;
      RECT 0.048 51.072 16.672 51.168 ;
      RECT 0.048 51.840 16.672 51.936 ;
      RECT 0.048 52.608 16.672 52.704 ;
      RECT 0.048 53.376 16.672 53.472 ;
      RECT 0.048 54.144 16.672 54.240 ;
      RECT 0.048 54.912 16.672 55.008 ;
      RECT 0.048 55.680 16.672 55.776 ;
      RECT 0.048 56.448 16.672 56.544 ;
      RECT 0.048 57.216 16.672 57.312 ;
      RECT 0.048 57.984 16.672 58.080 ;
      RECT 0.048 58.752 16.672 58.848 ;
      RECT 0.048 59.520 16.672 59.616 ;
      RECT 0.048 60.288 16.672 60.384 ;
      RECT 0.048 61.056 16.672 61.152 ;
      RECT 0.048 61.824 16.672 61.920 ;
      RECT 0.048 62.592 16.672 62.688 ;
      RECT 0.048 63.360 16.672 63.456 ;
      RECT 0.048 64.128 16.672 64.224 ;
      RECT 0.048 64.896 16.672 64.992 ;
      RECT 0.048 65.664 16.672 65.760 ;
      RECT 0.048 66.432 16.672 66.528 ;
      RECT 0.048 67.200 16.672 67.296 ;
      RECT 0.048 67.968 16.672 68.064 ;
      RECT 0.048 68.736 16.672 68.832 ;
      RECT 0.048 69.504 16.672 69.600 ;
      RECT 0.048 70.272 16.672 70.368 ;
      RECT 0.048 71.040 16.672 71.136 ;
      RECT 0.048 71.808 16.672 71.904 ;
      RECT 0.048 72.576 16.672 72.672 ;
      RECT 0.048 73.344 16.672 73.440 ;
      RECT 0.048 74.112 16.672 74.208 ;
      RECT 0.048 74.880 16.672 74.976 ;
      RECT 0.048 75.648 16.672 75.744 ;
      RECT 0.048 76.416 16.672 76.512 ;
      RECT 0.048 77.184 16.672 77.280 ;
      RECT 0.048 77.952 16.672 78.048 ;
      RECT 0.048 78.720 16.672 78.816 ;
      RECT 0.048 79.488 16.672 79.584 ;
      RECT 0.048 80.256 16.672 80.352 ;
      RECT 0.048 81.024 16.672 81.120 ;
      RECT 0.048 81.792 16.672 81.888 ;
      RECT 0.048 82.560 16.672 82.656 ;
      RECT 0.048 83.328 16.672 83.424 ;
    END
  END VDD
  OBS
    LAYER M1 ;
    RECT 0 0 16.720 84.000 ;
    LAYER M2 ;
    RECT 0 0 16.720 84.000 ;
    LAYER M3 ;
    RECT 0 0 16.720 84.000 ;
    LAYER M4 ;
    RECT 0 0 16.720 84.000 ;
  END
END sram_asap7_64x512_1rw

END LIBRARY
